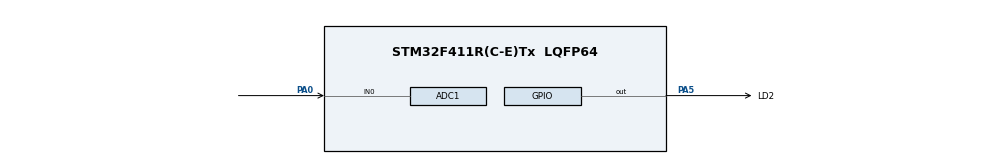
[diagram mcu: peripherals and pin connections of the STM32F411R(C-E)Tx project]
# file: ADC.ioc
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ADC1.Channel-2\#ChannelRegularConversion=ADC_CHANNEL_0
ADC1.ExternalTrigConv=ADC_EXTERNALTRIGCONV_T2_TRGO
ADC1.NbrOfConversion=1
ADC1.NbrOfConversionFlag=1
ADC1.Rank-2\#ChannelRegularConversion=1
ADC1.SamplingTime-2\#ChannelRegularConversion=ADC_SAMPLETIME_84CYCLES
ADC1.master=1
Mcu.Family=STM32F4
Mcu.Name=STM32F411R(C-E)Tx
Mcu.Package=LQFP64
NVIC.ADC_IRQn=true\:0\:0\:false\:false\:true\:true\:true\:true
NVIC.PriorityGroup=NVIC_PRIORITYGROUP_0
NVIC.TIM2_IRQn=true\:0\:0\:false\:false\:true\:true\:true\:true
PA0-WKUP.Signal=ADCx_IN0
PA13.GPIO_Label=TMS
PA13.Signal=SYS_JTMS-SWDIO
PA14.GPIO_Label=TCK
PA14.Signal=SYS_JTCK-SWCLK
PA5.GPIO_Label=LD2
PA5.Signal=GPIO_Output
PB3.GPIO_Label=SWO
PB3.Signal=SYS_JTDO-SWO
PC14-OSC32_IN.Signal=RCC_OSC32_IN
PC15-OSC32_OUT.Signal=RCC_OSC32_OUT
PH0\ -\ OSC_IN.Signal=RCC_OSC_IN
PH1\ -\ OSC_OUT.Signal=RCC_OSC_OUT
ProjectManager.HeapSize=0x200
ProjectManager.StackSize=0x400
ProjectManager.TargetToolchain=STM32CubeIDE
RCC.48MHZClocksFreq_Value=84000000
RCC.AHBFreq_Value=16000000
RCC.APB1CLKDivider=RCC_HCLK_DIV2
RCC.APB1Freq_Value=8000000
RCC.APB1TimFreq_Value=16000000
RCC.APB2CLKDivider=RCC_HCLK_DIV2
RCC.APB2Freq_Value=8000000
RCC.APB2TimFreq_Value=16000000
RCC.CortexFreq_Value=16000000
RCC.FLatency-AdvancedSettings=FLASH_LATENCY_0
RCC.HCLKFreq_Value=16000000
RCC.HSE_VALUE=8000000
RCC.HSI_VALUE=16000000
RCC.LSE_VALUE=32768
RCC.PLLN=336
RCC.PLLP=RCC_PLLP_DIV4
RCC.SYSCLKFreq_VALUE=16000000
RCC.VCOOutputFreq_Value=336000000
SH.ADCx_IN0.0=ADC1_IN0,IN0
TIM2.Period=50
TIM2.Prescaler=4800
VP_TIM2_VS_ClockSourceINT.Mode=Internal
board=NUCLEO-F411RE

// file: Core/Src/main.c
/* USER CODE BEGIN Header */
/**
  **************************
  * @file           : main.c
  * @brief          : Main program body
  **************************
  * @attention
  *
  * Copyright (c) 2022 STMicroelectronics.
  * All rights reserved.
  *
  * This software is licensed under terms that can be found in the LICENSE file
  * in the root directory of this software component.
  * If no LICENSE file comes with this software, it is provided AS-IS.
  *
  **************************
  */
/* USER CODE END Header */
#include "main.h"

ADC_HandleTypeDef hadc1;

TIM_HandleTypeDef htim2;

void SystemClock_Config(void);
static void MX_GPIO_Init(void);
static void MX_ADC1_Init(void);
static void MX_TIM2_Init(void);
/* USER CODE BEGIN PFP */
uint16_t Sensorval;
/* USER CODE END PFP */

int main(void)
{

  /* MCU Configuration--------------------------------------------------------*/

  /* Reset of all peripherals, Initializes the Flash interface and the Systick. */
  HAL_Init();

  /* Configure the system clock */
  SystemClock_Config();

  /* Initialize all configured peripherals */
  MX_GPIO_Init();
  MX_ADC1_Init();
  MX_TIM2_Init();
  /* USER CODE BEGIN 2 */
  //HAL_ADC_Start_IT(&hadc1);
  HAL_TIM_Base_Start_IT(&htim2);
  HAL_ADC_Start_IT(&hadc1);
  /* USER CODE END 2 */

  /* Infinite loop */
  while (1)
  {

  }
}
void HAL_ADC_ConvCpltCallback(ADC_HandleTypeDef* hadc)
{
	Sensorval = HAL_ADC_GetValue(&hadc1);
}
void SystemClock_Config(void)
{
  RCC_OscInitTypeDef RCC_OscInitStruct = {0};
  RCC_ClkInitTypeDef RCC_ClkInitStruct = {0};

  /** Configure the main internal regulator output voltage
  */
  __HAL_RCC_PWR_CLK_ENABLE();
  __HAL_PWR_VOLTAGESCALING_CONFIG(PWR_REGULATOR_VOLTAGE_SCALE1);

  /** Initializes the RCC Oscillators according to the specified parameters
  * in the RCC_OscInitTypeDef structure.
  */
  RCC_OscInitStruct.OscillatorType = RCC_OSCILLATORTYPE_HSI;
  RCC_OscInitStruct.HSIState = RCC_HSI_ON;
  RCC_OscInitStruct.HSICalibrationValue = RCC_HSICALIBRATION_DEFAULT;
  RCC_OscInitStruct.PLL.PLLState = RCC_PLL_NONE;
  if (HAL_RCC_OscConfig(&RCC_OscInitStruct) != HAL_OK)
  {
    Error_Handler();
  }

  /** Initializes the CPU, AHB and APB buses clocks
  */
  RCC_ClkInitStruct.ClockType = RCC_CLOCKTYPE_HCLK|RCC_CLOCKTYPE_SYSCLK
                              |RCC_CLOCKTYPE_PCLK1|RCC_CLOCKTYPE_PCLK2;
  RCC_ClkInitStruct.SYSCLKSource = RCC_SYSCLKSOURCE_HSI;
  RCC_ClkInitStruct.AHBCLKDivider = RCC_SYSCLK_DIV1;
  RCC_ClkInitStruct.APB1CLKDivider = RCC_HCLK_DIV2;
  RCC_ClkInitStruct.APB2CLKDivider = RCC_HCLK_DIV1;

  if (HAL_RCC_ClockConfig(&RCC_ClkInitStruct, FLASH_LATENCY_0) != HAL_OK)
  {
    Error_Handler();
  }
}

static void MX_ADC1_Init(void)
{

  ADC_ChannelConfTypeDef sConfig = {0};

  /** Configure the global features of the ADC (Clock, Resolution, Data Alignment and number of conversion)
  */
  hadc1.Instance = ADC1;
  hadc1.Init.ClockPrescaler = ADC_CLOCK_SYNC_PCLK_DIV2;
  hadc1.Init.Resolution = ADC_RESOLUTION_12B;
  hadc1.Init.ScanConvMode = DISABLE;
  hadc1.Init.ContinuousConvMode = DISABLE;
  hadc1.Init.DiscontinuousConvMode = DISABLE;
  hadc1.Init.ExternalTrigConvEdge = ADC_EXTERNALTRIGCONVEDGE_RISING;
  hadc1.Init.ExternalTrigConv = ADC_EXTERNALTRIGCONV_T2_TRGO;
  hadc1.Init.DataAlign = ADC_DATAALIGN_RIGHT;
  hadc1.Init.NbrOfConversion = 1;
  hadc1.Init.DMAContinuousRequests = DISABLE;
  hadc1.Init.EOCSelection = ADC_EOC_SINGLE_CONV;
  if (HAL_ADC_Init(&hadc1) != HAL_OK)
  {
    Error_Handler();
  }

  /** Configure for the selected ADC regular channel its corresponding rank in the sequencer and its sample time.
  */
  sConfig.Channel = ADC_CHANNEL_0;
  sConfig.Rank = 1;
  sConfig.SamplingTime = ADC_SAMPLETIME_84CYCLES;
  if (HAL_ADC_ConfigChannel(&hadc1, &sConfig) != HAL_OK)
  {
    Error_Handler();
  }

}

static void MX_TIM2_Init(void)
{

  TIM_ClockConfigTypeDef sClockSourceConfig = {0};
  TIM_MasterConfigTypeDef sMasterConfig = {0};

  htim2.Instance = TIM2;
  htim2.Init.Prescaler = 4800;
  htim2.Init.CounterMode = TIM_COUNTERMODE_UP;
  htim2.Init.Period = 50;
  htim2.Init.ClockDivision = TIM_CLOCKDIVISION_DIV1;
  htim2.Init.AutoReloadPreload = TIM_AUTORELOAD_PRELOAD_DISABLE;
  if (HAL_TIM_Base_Init(&htim2) != HAL_OK)
  {
    Error_Handler();
  }
  sClockSourceConfig.ClockSource = TIM_CLOCKSOURCE_INTERNAL;
  if (HAL_TIM_ConfigClockSource(&htim2, &sClockSourceConfig) != HAL_OK)
  {
    Error_Handler();
  }
  sMasterConfig.MasterOutputTrigger = TIM_TRGO_RESET;
  sMasterConfig.MasterSlaveMode = TIM_MASTERSLAVEMODE_DISABLE;
  if (HAL_TIMEx_MasterConfigSynchronization(&htim2, &sMasterConfig) != HAL_OK)
  {
    Error_Handler();
  }

}

static void MX_GPIO_Init(void)
{
  GPIO_InitTypeDef GPIO_InitStruct = {0};

  /* GPIO Ports Clock Enable */
  __HAL_RCC_GPIOC_CLK_ENABLE();
  __HAL_RCC_GPIOH_CLK_ENABLE();
  __HAL_RCC_GPIOA_CLK_ENABLE();
  __HAL_RCC_GPIOB_CLK_ENABLE();

  /*Configure GPIO pin Output Level */
  HAL_GPIO_WritePin(LD2_GPIO_Port, LD2_Pin, GPIO_PIN_RESET);

  /*Configure GPIO pin : LD2_Pin */
  GPIO_InitStruct.Pin = LD2_Pin;
  GPIO_InitStruct.Mode = GPIO_MODE_OUTPUT_PP;
  GPIO_InitStruct.Pull = GPIO_NOPULL;
  GPIO_InitStruct.Speed = GPIO_SPEED_FREQ_LOW;
  HAL_GPIO_Init(LD2_GPIO_Port, &GPIO_InitStruct);

}

void Error_Handler(void)
{
  __disable_irq();
  while (1)
  {
  }
}
